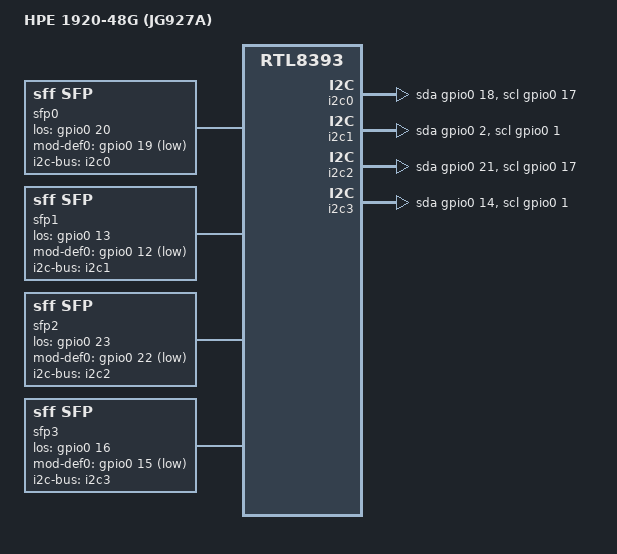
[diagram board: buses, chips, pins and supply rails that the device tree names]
// SPDX-License-Identifier: GPL-2.0-or-later OR MIT

#include "rtl8393_hpe_1920.dtsi"

/ {
	compatible = "hpe,1920-48g", "realtek,rtl8393-soc";
	model = "HPE 1920-48G (JG927A)";

	i2c0: i2c-gpio-0 {
		compatible = "i2c-gpio";
		sda-gpios = <&gpio0 18 (GPIO_ACTIVE_HIGH | GPIO_OPEN_DRAIN)>;
		scl-gpios = <&gpio0 17 (GPIO_ACTIVE_HIGH | GPIO_OPEN_DRAIN)>;
		i2c-gpio,delay-us = <2>;
		#address-cells = <1>;
		#size-cells = <0>;
	};

	i2c1: i2c-gpio-1 {
		compatible = "i2c-gpio";
		sda-gpios = <&gpio0 2 (GPIO_ACTIVE_HIGH | GPIO_OPEN_DRAIN)>;
		scl-gpios = <&gpio0 1 (GPIO_ACTIVE_HIGH | GPIO_OPEN_DRAIN)>;
		i2c-gpio,delay-us = <2>;
		#address-cells = <1>;
		#size-cells = <0>;
	};

	i2c2: i2c-gpio-2 {
		compatible = "i2c-gpio";
		sda-gpios = <&gpio0 21 (GPIO_ACTIVE_HIGH | GPIO_OPEN_DRAIN)>;
		scl-gpios = <&gpio0 17 (GPIO_ACTIVE_HIGH | GPIO_OPEN_DRAIN)>;
		i2c-gpio,delay-us = <2>;
		#address-cells = <1>;
		#size-cells = <0>;
	};

	i2c3: i2c-gpio-3 {
		compatible = "i2c-gpio";
		sda-gpios = <&gpio0 14 (GPIO_ACTIVE_HIGH | GPIO_OPEN_DRAIN)>;
		scl-gpios = <&gpio0 1 (GPIO_ACTIVE_HIGH | GPIO_OPEN_DRAIN)>;
		i2c-gpio,delay-us = <2>;
		#address-cells = <1>;
		#size-cells = <0>;
	};

	sfp0: sfp-p49 {
		compatible = "sff,sfp";
		i2c-bus = <&i2c0>;
		los-gpio = <&gpio0 20 GPIO_ACTIVE_HIGH>;
		mod-def0-gpio = <&gpio0 19 GPIO_ACTIVE_LOW>;
		// tx-fault unconnected (TODO?)
		// tx-disable connected to RTL8214FC (TODO?)
	};

	sfp1: sfp-p50 {
		compatible = "sff,sfp";
		i2c-bus = <&i2c1>;
		los-gpio = <&gpio0 13 GPIO_ACTIVE_HIGH>;
		mod-def0-gpio = <&gpio0 12 GPIO_ACTIVE_LOW>;
		// tx-fault unconnected (TODO?)
		// tx-disable connected to RTL8214FC (TODO?)
	};

	sfp2: sfp-p51 {
		compatible = "sff,sfp";
		i2c-bus = <&i2c2>;
		los-gpio = <&gpio0 23 GPIO_ACTIVE_HIGH>;
		mod-def0-gpio = <&gpio0 22 GPIO_ACTIVE_LOW>;
		// tx-fault unconnected (TODO?)
		// tx-disable connected to RTL8214FC (TODO?)
	};

	sfp3: sfp-p52 {
		compatible = "sff,sfp";
		i2c-bus = <&i2c3>;
		los-gpio = <&gpio0 16 GPIO_ACTIVE_HIGH>;
		mod-def0-gpio = <&gpio0 15 GPIO_ACTIVE_LOW>;
		// tx-fault unconnected (TODO?)
		// tx-disable connected to RTL8214FC (TODO?)
	};

};

&mdio_bus1 {
	PHY_C22_SFP(48, 24, 1)
	PHY_C22_SFP(49, 25, 3)
	PHY_C22_SFP(50, 26, 0)
	PHY_C22_SFP(51, 27, 2)
};

&switch0 {
	ethernet-ports {
		SWITCH_PORT_SDS(48, 50, 12, 0, qsgmii)
		SWITCH_PORT_SDS(49, 52, 12, 1, qsgmii)
		SWITCH_PORT_SDS(50, 49, 12, 2, qsgmii)
		SWITCH_PORT_SDS(51, 51, 12, 3, qsgmii)
	};
};

&port48 {
	nvmem-cells = <&macaddr_factory 51>;
	nvmem-cell-names = "mac-address";
};

&port49 {
	nvmem-cells = <&macaddr_factory 53>;
	nvmem-cell-names = "mac-address";
};

&port50 {
	nvmem-cells = <&macaddr_factory 50>;
	nvmem-cell-names = "mac-address";
};

&port51 {
	nvmem-cells = <&macaddr_factory 52>;
	nvmem-cell-names = "mac-address";
};
